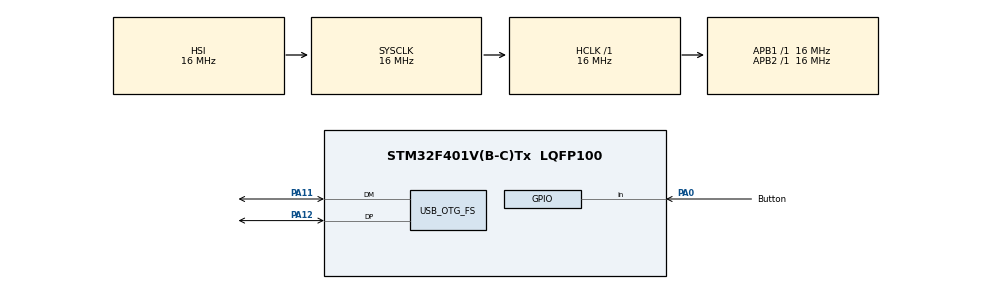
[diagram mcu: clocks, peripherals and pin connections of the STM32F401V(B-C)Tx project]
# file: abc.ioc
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Mcu.Family=STM32F4
Mcu.Name=STM32F401V(B-C)Tx
Mcu.Package=LQFP100
NVIC.OTG_FS_IRQn=true\:0\:0\:false\:false\:true\:false
NVIC.PriorityGroup=NVIC_PRIORITYGROUP_4
PA0-WKUP.GPIO_Label=Button
PA0-WKUP.Signal=GPIO_Input
PA11.Mode=Device_Only
PA11.Signal=USB_OTG_FS_DM
PA12.Mode=Device_Only
PA12.Signal=USB_OTG_FS_DP
PH0\ -\ OSC_IN.Mode=HSE-External-Oscillator
PH0\ -\ OSC_IN.Signal=RCC_OSC_IN
PH1\ -\ OSC_OUT.Mode=HSE-External-Oscillator
PH1\ -\ OSC_OUT.Signal=RCC_OSC_OUT
ProjectManager.HeapSize=0x200
ProjectManager.StackSize=0x400
ProjectManager.TargetToolchain=TrueSTUDIO
RCC.48MHZClocksFreq_Value=48000000
RCC.AHBFreq_Value=16000000
RCC.APB1Freq_Value=16000000
RCC.APB2Freq_Value=16000000
RCC.CortexFreq_Value=16000000
RCC.HSE_VALUE=25000000
RCC.HSI_VALUE=16000000
RCC.LSE_VALUE=32768
RCC.PLLM=15
RCC.PLLN=144
RCC.PLLQ=5
RCC.SYSCLKFreq_VALUE=16000000
RCC.VCOOutputFreq_Value=240000000
USB_DEVICE.APP_RX_DATA_SIZE=1000
USB_DEVICE.APP_RX_DATA_SIZE-CDC_FS=2048
USB_DEVICE.APP_TX_DATA_SIZE=1000
USB_DEVICE.APP_TX_DATA_SIZE-CDC_FS=2048
USB_DEVICE.CLASS_NAME_FS=CDC
USB_DEVICE.VirtualMode=Cdc
USB_DEVICE.VirtualMode-CDC_FS=Cdc
USB_DEVICE.VirtualModeFS=Cdc_FS
USB_OTG_FS.VirtualMode=Device_Only
USB_OTG_FS.ep0_mps=DEP0CTL_MPS_64
USB_OTG_FS.vbus_sensing_enable=DISABLE
VP_USB_DEVICE_VS_USB_DEVICE_CDC_FS.Mode=CDC_FS
board=abc

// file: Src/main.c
/**
  ******************************************************************************
  * @file           : main.c
  * @brief          : Main program body
  ******************************************************************************
  * This notice applies to any and all portions of this file
  * that are not between comment pairs USER CODE BEGIN and
  * USER CODE END. Other portions of this file, whether
  * inserted by the user or by software development tools
  * are owned by their respective copyright owners.
  *
  * Copyright (c) 2018 STMicroelectronics International N.V.
  * All rights reserved.
  *
  * Redistribution and use in source and binary forms, with or without
  * modification, are permitted, provided that the following conditions are met:
  *
  * 1. Redistribution of source code must retain the above copyright notice,
  *    this list of conditions and the following disclaimer.
  * 2. Redistributions in binary form must reproduce the above copyright notice,
  *    this list of conditions and the following disclaimer in the documentation
  *    and/or other materials provided with the distribution.
  * 3. Neither the name of STMicroelectronics nor the names of other
  *    contributors to this software may be used to endorse or promote products
  *    derived from this software without specific written permission.
  * 4. This software, including modifications and/or derivative works of this
  *    software, must execute solely and exclusively on microcontroller or
  *    microprocessor devices manufactured by or for STMicroelectronics.
  * 5. Redistribution and use of this software other than as permitted under
  *    this license is void and will automatically terminate your rights under
  *    this license.
  *
  * THIS SOFTWARE IS PROVIDED BY STMICROELECTRONICS AND CONTRIBUTORS "AS IS"
  * AND ANY EXPRESS, IMPLIED OR STATUTORY WARRANTIES, INCLUDING, BUT NOT
  * LIMITED TO, THE IMPLIED WARRANTIES OF MERCHANTABILITY, FITNESS FOR A
  * PARTICULAR PURPOSE AND NON-INFRINGEMENT OF THIRD PARTY INTELLECTUAL PROPERTY
  * RIGHTS ARE DISCLAIMED TO THE FULLEST EXTENT PERMITTED BY LAW. IN NO EVENT
  * SHALL STMICROELECTRONICS OR CONTRIBUTORS BE LIABLE FOR ANY DIRECT, INDIRECT,
  * INCIDENTAL, SPECIAL, EXEMPLARY, OR CONSEQUENTIAL DAMAGES (INCLUDING, BUT NOT
  * LIMITED TO, PROCUREMENT OF SUBSTITUTE GOODS OR SERVICES; LOSS OF USE, DATA,
  * OR PROFITS; OR BUSINESS INTERRUPTION) HOWEVER CAUSED AND ON ANY THEORY OF
  * LIABILITY, WHETHER IN CONTRACT, STRICT LIABILITY, OR TORT (INCLUDING
  * NEGLIGENCE OR OTHERWISE) ARISING IN ANY WAY OUT OF THE USE OF THIS SOFTWARE,
  * EVEN IF ADVISED OF THE POSSIBILITY OF SUCH DAMAGE.
  *
  ******************************************************************************
  */
#include "main.h"
#include "stm32f4xx_hal.h"
#include "usb_device.h"

/* USER CODE BEGIN Includes */
#include "usbd_cdc_if.h" // Plik bedacy interfejsem uzytkownika do kontrolera USB
/* USER CODE END Includes */

#define FILEADDR 0x8010000
#define DATAOFFSET 0x5E
#define DATAEND 0x2AEB8

/* USER CODE BEGIN PV */
/* Private variables ---------------------------------------------------------*/
uint8_t DataToSend[80]; // Tablica zawierajaca dane do wyslania

uint8_t ReceivedData[80]; // Tablica przechowujaca odebrane dane
uint8_t ReceivedDataFlag = 0; // Flaga informujaca o odebraniu danych
uint32_t fileindex=0;
uint8_t dct=0;

uint8_t l1[3]={0,1,1};
uint8_t l2[3]={0,0,1};
/* USER CODE END PV */

void SystemClock_Config(void);
static void MX_GPIO_Init(void);
extern void mixer(uint8_t* inPtr, uint8_t* srcPtr, uint8_t* outPtr, int volumeDown);

/* USER CODE BEGIN PFP */
/* Private function prototypes -----------------------------------------------*/

/* USER CODE END PFP */

int main(void)
{

  /* MCU Configuration----------------------------------------------------------*/

  /* Reset of all peripherals, Initializes the Flash interface and the Systick. */
  HAL_Init();

  /* Configure the system clock */
  SystemClock_Config();

  /* Initialize all configured peripherals */

  MX_GPIO_Init();

  MX_USB_DEVICE_Init();

  /* Infinite loop */
  /* USER CODE BEGIN WHILE */

  uint8_t md=0;

  while (1) {

   if(dct==100){
	   md++;
	   if(md==3) md=0;
	   HAL_GPIO_WritePin(BlueLED_GPIO_Port, BlueLED_Pin, l1[md]);
	   HAL_GPIO_WritePin(GreenLED_GPIO_Port, GreenLED_Pin, l2[md]);
	   dct=0;
   }

   if(ReceivedDataFlag == 1){
	   ReceivedDataFlag = 0;
	   uint8_t* fileStart = (uint8_t *) FILEADDR + DATAOFFSET + fileindex;
	   mixer(fileStart, ReceivedData, ReceivedData, md);
	   fileindex += 60;
	   if (fileindex == DATAEND)
		   fileindex = 0;
	   while(CDC_Transmit_FS(ReceivedData, 60) == USBD_BUSY);
     }

  }
  /* USER CODE END 3 */

}

void SystemClock_Config(void)
{

  RCC_OscInitTypeDef RCC_OscInitStruct;
  RCC_ClkInitTypeDef RCC_ClkInitStruct;

    /**Configure the main internal regulator output voltage
    */
  __HAL_RCC_PWR_CLK_ENABLE();

  __HAL_PWR_VOLTAGESCALING_CONFIG(PWR_REGULATOR_VOLTAGE_SCALE1);

    /**Initializes the CPU, AHB and APB busses clocks
    */
  RCC_OscInitStruct.OscillatorType = RCC_OSCILLATORTYPE_HSI|RCC_OSCILLATORTYPE_HSE;
  RCC_OscInitStruct.HSEState = RCC_HSE_ON;
  RCC_OscInitStruct.HSIState = RCC_HSI_ON;
  RCC_OscInitStruct.HSICalibrationValue = 16;
  RCC_OscInitStruct.PLL.PLLState = RCC_PLL_ON;
  RCC_OscInitStruct.PLL.PLLSource = RCC_PLLSOURCE_HSE;
  RCC_OscInitStruct.PLL.PLLM = 4;
  RCC_OscInitStruct.PLL.PLLN = 72;
  RCC_OscInitStruct.PLL.PLLP = RCC_PLLP_DIV2;
  RCC_OscInitStruct.PLL.PLLQ = 3;
  if (HAL_RCC_OscConfig(&RCC_OscInitStruct) != HAL_OK)
  {
    _Error_Handler(__FILE__, __LINE__);
  }

    /**Initializes the CPU, AHB and APB busses clocks
    */
  RCC_ClkInitStruct.ClockType = RCC_CLOCKTYPE_HCLK|RCC_CLOCKTYPE_SYSCLK
                              |RCC_CLOCKTYPE_PCLK1|RCC_CLOCKTYPE_PCLK2;
  RCC_ClkInitStruct.SYSCLKSource = RCC_SYSCLKSOURCE_HSI;
  RCC_ClkInitStruct.AHBCLKDivider = RCC_SYSCLK_DIV1;
  RCC_ClkInitStruct.APB1CLKDivider = RCC_HCLK_DIV1;
  RCC_ClkInitStruct.APB2CLKDivider = RCC_HCLK_DIV1;

  if (HAL_RCC_ClockConfig(&RCC_ClkInitStruct, FLASH_LATENCY_0) != HAL_OK)
  {
    _Error_Handler(__FILE__, __LINE__);
  }

    /**Configure the Systick interrupt time
    */
  HAL_SYSTICK_Config(HAL_RCC_GetHCLKFreq()/1000);

    /**Configure the Systick
    */
  HAL_SYSTICK_CLKSourceConfig(SYSTICK_CLKSOURCE_HCLK);

  /* SysTick_IRQn interrupt configuration */
  HAL_NVIC_SetPriority(SysTick_IRQn, 0, 0);
}

/** Configure pins as
        * Analog
        * Input
        * Output
        * EVENT_OUT
        * EXTI
*/
static void MX_GPIO_Init(void)
{

  GPIO_InitTypeDef GPIO_InitStruct;

  /* GPIO Ports Clock Enable */
  __HAL_RCC_GPIOH_CLK_ENABLE();
  __HAL_RCC_GPIOA_CLK_ENABLE();
  __HAL_RCC_GPIOD_CLK_ENABLE();

  /*Configure GPIO pin Output Level */
  HAL_GPIO_WritePin(GPIOD, GreenLED_Pin|OrangeLED_Pin|RedLED_Pin|BlueLED_Pin, GPIO_PIN_RESET);

  /*Configure GPIO pin : Button_Pin */
  GPIO_InitStruct.Pin = Button_Pin;
  GPIO_InitStruct.Mode = GPIO_MODE_INPUT;
  GPIO_InitStruct.Pull = GPIO_NOPULL;
  HAL_GPIO_Init(Button_GPIO_Port, &GPIO_InitStruct);

  /*Configure GPIO pins : GreenLED_Pin OrangeLED_Pin RedLED_Pin BlueLED_Pin */
  GPIO_InitStruct.Pin = GreenLED_Pin|OrangeLED_Pin|RedLED_Pin|BlueLED_Pin;
  GPIO_InitStruct.Mode = GPIO_MODE_OUTPUT_PP;
  GPIO_InitStruct.Pull = GPIO_NOPULL;
  GPIO_InitStruct.Speed = GPIO_SPEED_FREQ_LOW;
  HAL_GPIO_Init(GPIOD, &GPIO_InitStruct);

}

void _Error_Handler(char *file, int line)
{
  while(1)
  {
  }
}

/************************ (C) COPYRIGHT STMicroelectronics *****END OF FILE****/
